# Generated by FakeRAM 2.0
VERSION 5.7 ;
BUSBITCHARS "[]" ;
PROPERTYDEFINITIONS
  MACRO width INTEGER ;
  MACRO depth INTEGER ;
  MACRO banks INTEGER ;
END PROPERTYDEFINITIONS
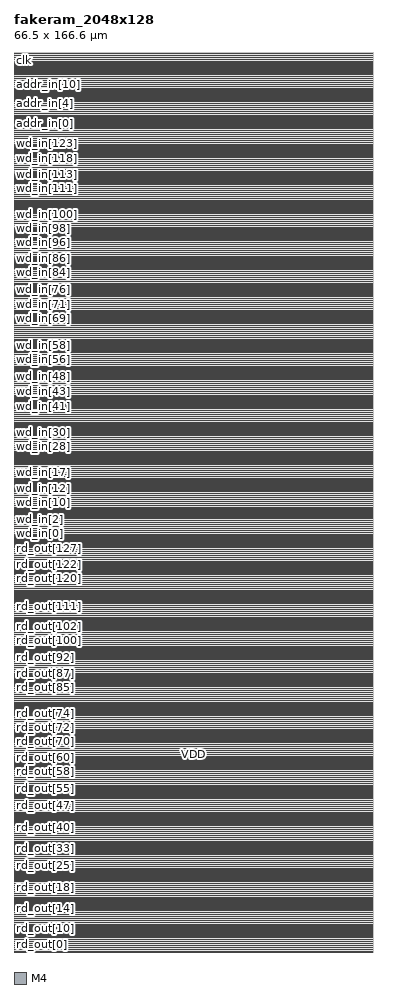
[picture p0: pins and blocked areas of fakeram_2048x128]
MACRO fakeram_2048x128
  PROPERTY width 128 ;
  PROPERTY depth 2048 ;
  PROPERTY banks 4 ;
  FOREIGN fakeram_2048x128 0 0 ;
  SYMMETRY X Y R90 ;
  SIZE 66.500 BY 166.600 ;
  CLASS BLOCK ;
  PIN rd_out[0]
    DIRECTION OUTPUT ;
    USE SIGNAL ;
    SHAPE ABUTMENT ;
    PORT
      LAYER M4 ;
      RECT 0.000 0.048 0.024 0.072 ;
    END
  END rd_out[0]
  PIN rd_out[1]
    DIRECTION OUTPUT ;
    USE SIGNAL ;
    SHAPE ABUTMENT ;
    PORT
      LAYER M4 ;
      RECT 0.000 0.624 0.024 0.648 ;
    END
  END rd_out[1]
  PIN rd_out[2]
    DIRECTION OUTPUT ;
    USE SIGNAL ;
    SHAPE ABUTMENT ;
    PORT
      LAYER M4 ;
      RECT 0.000 1.200 0.024 1.224 ;
    END
  END rd_out[2]
  PIN rd_out[3]
    DIRECTION OUTPUT ;
    USE SIGNAL ;
    SHAPE ABUTMENT ;
    PORT
      LAYER M4 ;
      RECT 0.000 1.776 0.024 1.800 ;
    END
  END rd_out[3]
  PIN rd_out[4]
    DIRECTION OUTPUT ;
    USE SIGNAL ;
    SHAPE ABUTMENT ;
    PORT
      LAYER M4 ;
      RECT 0.000 2.352 0.024 2.376 ;
    END
  END rd_out[4]
  PIN rd_out[5]
    DIRECTION OUTPUT ;
    USE SIGNAL ;
    SHAPE ABUTMENT ;
    PORT
      LAYER M4 ;
      RECT 0.000 2.928 0.024 2.952 ;
    END
  END rd_out[5]
  PIN rd_out[6]
    DIRECTION OUTPUT ;
    USE SIGNAL ;
    SHAPE ABUTMENT ;
    PORT
      LAYER M4 ;
      RECT 0.000 3.504 0.024 3.528 ;
    END
  END rd_out[6]
  PIN rd_out[7]
    DIRECTION OUTPUT ;
    USE SIGNAL ;
    SHAPE ABUTMENT ;
    PORT
      LAYER M4 ;
      RECT 0.000 4.080 0.024 4.104 ;
    END
  END rd_out[7]
  PIN rd_out[8]
    DIRECTION OUTPUT ;
    USE SIGNAL ;
    SHAPE ABUTMENT ;
    PORT
      LAYER M4 ;
      RECT 0.000 4.656 0.024 4.680 ;
    END
  END rd_out[8]
  PIN rd_out[9]
    DIRECTION OUTPUT ;
    USE SIGNAL ;
    SHAPE ABUTMENT ;
    PORT
      LAYER M4 ;
      RECT 0.000 5.232 0.024 5.256 ;
    END
  END rd_out[9]
  PIN rd_out[10]
    DIRECTION OUTPUT ;
    USE SIGNAL ;
    SHAPE ABUTMENT ;
    PORT
      LAYER M4 ;
      RECT 0.000 5.808 0.024 5.832 ;
    END
  END rd_out[10]
  PIN rd_out[11]
    DIRECTION OUTPUT ;
    USE SIGNAL ;
    SHAPE ABUTMENT ;
    PORT
      LAYER M4 ;
      RECT 0.000 6.384 0.024 6.408 ;
    END
  END rd_out[11]
  PIN rd_out[12]
    DIRECTION OUTPUT ;
    USE SIGNAL ;
    SHAPE ABUTMENT ;
    PORT
      LAYER M4 ;
      RECT 0.000 6.960 0.024 6.984 ;
    END
  END rd_out[12]
  PIN rd_out[13]
    DIRECTION OUTPUT ;
    USE SIGNAL ;
    SHAPE ABUTMENT ;
    PORT
      LAYER M4 ;
      RECT 0.000 7.536 0.024 7.560 ;
    END
  END rd_out[13]
  PIN rd_out[14]
    DIRECTION OUTPUT ;
    USE SIGNAL ;
    SHAPE ABUTMENT ;
    PORT
      LAYER M4 ;
      RECT 0.000 8.112 0.024 8.136 ;
    END
  END rd_out[14]
  PIN rd_out[15]
    DIRECTION OUTPUT ;
    USE SIGNAL ;
    SHAPE ABUTMENT ;
    PORT
      LAYER M4 ;
      RECT 0.000 8.688 0.024 8.712 ;
    END
  END rd_out[15]
  PIN rd_out[16]
    DIRECTION OUTPUT ;
    USE SIGNAL ;
    SHAPE ABUTMENT ;
    PORT
      LAYER M4 ;
      RECT 0.000 9.264 0.024 9.288 ;
    END
  END rd_out[16]
  PIN rd_out[17]
    DIRECTION OUTPUT ;
    USE SIGNAL ;
    SHAPE ABUTMENT ;
    PORT
      LAYER M4 ;
      RECT 0.000 9.840 0.024 9.864 ;
    END
  END rd_out[17]
  PIN rd_out[18]
    DIRECTION OUTPUT ;
    USE SIGNAL ;
    SHAPE ABUTMENT ;
    PORT
      LAYER M4 ;
      RECT 0.000 10.416 0.024 10.440 ;
    END
  END rd_out[18]
  PIN rd_out[19]
    DIRECTION OUTPUT ;
    USE SIGNAL ;
    SHAPE ABUTMENT ;
    PORT
      LAYER M4 ;
      RECT 0.000 10.992 0.024 11.016 ;
    END
  END rd_out[19]
  PIN rd_out[20]
    DIRECTION OUTPUT ;
    USE SIGNAL ;
    SHAPE ABUTMENT ;
    PORT
      LAYER M4 ;
      RECT 0.000 11.568 0.024 11.592 ;
    END
  END rd_out[20]
  PIN rd_out[21]
    DIRECTION OUTPUT ;
    USE SIGNAL ;
    SHAPE ABUTMENT ;
    PORT
      LAYER M4 ;
      RECT 0.000 12.144 0.024 12.168 ;
    END
  END rd_out[21]
  PIN rd_out[22]
    DIRECTION OUTPUT ;
    USE SIGNAL ;
    SHAPE ABUTMENT ;
    PORT
      LAYER M4 ;
      RECT 0.000 12.720 0.024 12.744 ;
    END
  END rd_out[22]
  PIN rd_out[23]
    DIRECTION OUTPUT ;
    USE SIGNAL ;
    SHAPE ABUTMENT ;
    PORT
      LAYER M4 ;
      RECT 0.000 13.296 0.024 13.320 ;
    END
  END rd_out[23]
  PIN rd_out[24]
    DIRECTION OUTPUT ;
    USE SIGNAL ;
    SHAPE ABUTMENT ;
    PORT
      LAYER M4 ;
      RECT 0.000 13.872 0.024 13.896 ;
    END
  END rd_out[24]
  PIN rd_out[25]
    DIRECTION OUTPUT ;
    USE SIGNAL ;
    SHAPE ABUTMENT ;
    PORT
      LAYER M4 ;
      RECT 0.000 14.448 0.024 14.472 ;
    END
  END rd_out[25]
  PIN rd_out[26]
    DIRECTION OUTPUT ;
    USE SIGNAL ;
    SHAPE ABUTMENT ;
    PORT
      LAYER M4 ;
      RECT 0.000 15.024 0.024 15.048 ;
    END
  END rd_out[26]
  PIN rd_out[27]
    DIRECTION OUTPUT ;
    USE SIGNAL ;
    SHAPE ABUTMENT ;
    PORT
      LAYER M4 ;
      RECT 0.000 15.600 0.024 15.624 ;
    END
  END rd_out[27]
  PIN rd_out[28]
    DIRECTION OUTPUT ;
    USE SIGNAL ;
    SHAPE ABUTMENT ;
    PORT
      LAYER M4 ;
      RECT 0.000 16.176 0.024 16.200 ;
    END
  END rd_out[28]
  PIN rd_out[29]
    DIRECTION OUTPUT ;
    USE SIGNAL ;
    SHAPE ABUTMENT ;
    PORT
      LAYER M4 ;
      RECT 0.000 16.752 0.024 16.776 ;
    END
  END rd_out[29]
  PIN rd_out[30]
    DIRECTION OUTPUT ;
    USE SIGNAL ;
    SHAPE ABUTMENT ;
    PORT
      LAYER M4 ;
      RECT 0.000 17.328 0.024 17.352 ;
    END
  END rd_out[30]
  PIN rd_out[31]
    DIRECTION OUTPUT ;
    USE SIGNAL ;
    SHAPE ABUTMENT ;
    PORT
      LAYER M4 ;
      RECT 0.000 17.904 0.024 17.928 ;
    END
  END rd_out[31]
  PIN rd_out[32]
    DIRECTION OUTPUT ;
    USE SIGNAL ;
    SHAPE ABUTMENT ;
    PORT
      LAYER M4 ;
      RECT 0.000 18.480 0.024 18.504 ;
    END
  END rd_out[32]
  PIN rd_out[33]
    DIRECTION OUTPUT ;
    USE SIGNAL ;
    SHAPE ABUTMENT ;
    PORT
      LAYER M4 ;
      RECT 0.000 19.056 0.024 19.080 ;
    END
  END rd_out[33]
  PIN rd_out[34]
    DIRECTION OUTPUT ;
    USE SIGNAL ;
    SHAPE ABUTMENT ;
    PORT
      LAYER M4 ;
      RECT 0.000 19.632 0.024 19.656 ;
    END
  END rd_out[34]
  PIN rd_out[35]
    DIRECTION OUTPUT ;
    USE SIGNAL ;
    SHAPE ABUTMENT ;
    PORT
      LAYER M4 ;
      RECT 0.000 20.208 0.024 20.232 ;
    END
  END rd_out[35]
  PIN rd_out[36]
    DIRECTION OUTPUT ;
    USE SIGNAL ;
    SHAPE ABUTMENT ;
    PORT
      LAYER M4 ;
      RECT 0.000 20.784 0.024 20.808 ;
    END
  END rd_out[36]
  PIN rd_out[37]
    DIRECTION OUTPUT ;
    USE SIGNAL ;
    SHAPE ABUTMENT ;
    PORT
      LAYER M4 ;
      RECT 0.000 21.360 0.024 21.384 ;
    END
  END rd_out[37]
  PIN rd_out[38]
    DIRECTION OUTPUT ;
    USE SIGNAL ;
    SHAPE ABUTMENT ;
    PORT
      LAYER M4 ;
      RECT 0.000 21.936 0.024 21.960 ;
    END
  END rd_out[38]
  PIN rd_out[39]
    DIRECTION OUTPUT ;
    USE SIGNAL ;
    SHAPE ABUTMENT ;
    PORT
      LAYER M4 ;
      RECT 0.000 22.512 0.024 22.536 ;
    END
  END rd_out[39]
  PIN rd_out[40]
    DIRECTION OUTPUT ;
    USE SIGNAL ;
    SHAPE ABUTMENT ;
    PORT
      LAYER M4 ;
      RECT 0.000 23.088 0.024 23.112 ;
    END
  END rd_out[40]
  PIN rd_out[41]
    DIRECTION OUTPUT ;
    USE SIGNAL ;
    SHAPE ABUTMENT ;
    PORT
      LAYER M4 ;
      RECT 0.000 23.664 0.024 23.688 ;
    END
  END rd_out[41]
  PIN rd_out[42]
    DIRECTION OUTPUT ;
    USE SIGNAL ;
    SHAPE ABUTMENT ;
    PORT
      LAYER M4 ;
      RECT 0.000 24.240 0.024 24.264 ;
    END
  END rd_out[42]
  PIN rd_out[43]
    DIRECTION OUTPUT ;
    USE SIGNAL ;
    SHAPE ABUTMENT ;
    PORT
      LAYER M4 ;
      RECT 0.000 24.816 0.024 24.840 ;
    END
  END rd_out[43]
  PIN rd_out[44]
    DIRECTION OUTPUT ;
    USE SIGNAL ;
    SHAPE ABUTMENT ;
    PORT
      LAYER M4 ;
      RECT 0.000 25.392 0.024 25.416 ;
    END
  END rd_out[44]
  PIN rd_out[45]
    DIRECTION OUTPUT ;
    USE SIGNAL ;
    SHAPE ABUTMENT ;
    PORT
      LAYER M4 ;
      RECT 0.000 25.968 0.024 25.992 ;
    END
  END rd_out[45]
  PIN rd_out[46]
    DIRECTION OUTPUT ;
    USE SIGNAL ;
    SHAPE ABUTMENT ;
    PORT
      LAYER M4 ;
      RECT 0.000 26.544 0.024 26.568 ;
    END
  END rd_out[46]
  PIN rd_out[47]
    DIRECTION OUTPUT ;
    USE SIGNAL ;
    SHAPE ABUTMENT ;
    PORT
      LAYER M4 ;
      RECT 0.000 27.120 0.024 27.144 ;
    END
  END rd_out[47]
  PIN rd_out[48]
    DIRECTION OUTPUT ;
    USE SIGNAL ;
    SHAPE ABUTMENT ;
    PORT
      LAYER M4 ;
      RECT 0.000 27.696 0.024 27.720 ;
    END
  END rd_out[48]
  PIN rd_out[49]
    DIRECTION OUTPUT ;
    USE SIGNAL ;
    SHAPE ABUTMENT ;
    PORT
      LAYER M4 ;
      RECT 0.000 28.272 0.024 28.296 ;
    END
  END rd_out[49]
  PIN rd_out[50]
    DIRECTION OUTPUT ;
    USE SIGNAL ;
    SHAPE ABUTMENT ;
    PORT
      LAYER M4 ;
      RECT 0.000 28.848 0.024 28.872 ;
    END
  END rd_out[50]
  PIN rd_out[51]
    DIRECTION OUTPUT ;
    USE SIGNAL ;
    SHAPE ABUTMENT ;
    PORT
      LAYER M4 ;
      RECT 0.000 29.424 0.024 29.448 ;
    END
  END rd_out[51]
  PIN rd_out[52]
    DIRECTION OUTPUT ;
    USE SIGNAL ;
    SHAPE ABUTMENT ;
    PORT
      LAYER M4 ;
      RECT 0.000 30.000 0.024 30.024 ;
    END
  END rd_out[52]
  PIN rd_out[53]
    DIRECTION OUTPUT ;
    USE SIGNAL ;
    SHAPE ABUTMENT ;
    PORT
      LAYER M4 ;
      RECT 0.000 30.576 0.024 30.600 ;
    END
  END rd_out[53]
  PIN rd_out[54]
    DIRECTION OUTPUT ;
    USE SIGNAL ;
    SHAPE ABUTMENT ;
    PORT
      LAYER M4 ;
      RECT 0.000 31.152 0.024 31.176 ;
    END
  END rd_out[54]
  PIN rd_out[55]
    DIRECTION OUTPUT ;
    USE SIGNAL ;
    SHAPE ABUTMENT ;
    PORT
      LAYER M4 ;
      RECT 0.000 31.728 0.024 31.752 ;
    END
  END rd_out[55]
  PIN rd_out[56]
    DIRECTION OUTPUT ;
    USE SIGNAL ;
    SHAPE ABUTMENT ;
    PORT
      LAYER M4 ;
      RECT 0.000 32.304 0.024 32.328 ;
    END
  END rd_out[56]
  PIN rd_out[57]
    DIRECTION OUTPUT ;
    USE SIGNAL ;
    SHAPE ABUTMENT ;
    PORT
      LAYER M4 ;
      RECT 0.000 32.880 0.024 32.904 ;
    END
  END rd_out[57]
  PIN rd_out[58]
    DIRECTION OUTPUT ;
    USE SIGNAL ;
    SHAPE ABUTMENT ;
    PORT
      LAYER M4 ;
      RECT 0.000 33.456 0.024 33.480 ;
    END
  END rd_out[58]
  PIN rd_out[59]
    DIRECTION OUTPUT ;
    USE SIGNAL ;
    SHAPE ABUTMENT ;
    PORT
      LAYER M4 ;
      RECT 0.000 34.032 0.024 34.056 ;
    END
  END rd_out[59]
  PIN rd_out[60]
    DIRECTION OUTPUT ;
    USE SIGNAL ;
    SHAPE ABUTMENT ;
    PORT
      LAYER M4 ;
      RECT 0.000 34.608 0.024 34.632 ;
    END
  END rd_out[60]
  PIN rd_out[61]
    DIRECTION OUTPUT ;
    USE SIGNAL ;
    SHAPE ABUTMENT ;
    PORT
      LAYER M4 ;
      RECT 0.000 35.184 0.024 35.208 ;
    END
  END rd_out[61]
  PIN rd_out[62]
    DIRECTION OUTPUT ;
    USE SIGNAL ;
    SHAPE ABUTMENT ;
    PORT
      LAYER M4 ;
      RECT 0.000 35.760 0.024 35.784 ;
    END
  END rd_out[62]
  PIN rd_out[63]
    DIRECTION OUTPUT ;
    USE SIGNAL ;
    SHAPE ABUTMENT ;
    PORT
      LAYER M4 ;
      RECT 0.000 36.336 0.024 36.360 ;
    END
  END rd_out[63]
  PIN rd_out[64]
    DIRECTION OUTPUT ;
    USE SIGNAL ;
    SHAPE ABUTMENT ;
    PORT
      LAYER M4 ;
      RECT 0.000 36.912 0.024 36.936 ;
    END
  END rd_out[64]
  PIN rd_out[65]
    DIRECTION OUTPUT ;
    USE SIGNAL ;
    SHAPE ABUTMENT ;
    PORT
      LAYER M4 ;
      RECT 0.000 37.488 0.024 37.512 ;
    END
  END rd_out[65]
  PIN rd_out[66]
    DIRECTION OUTPUT ;
    USE SIGNAL ;
    SHAPE ABUTMENT ;
    PORT
      LAYER M4 ;
      RECT 0.000 38.064 0.024 38.088 ;
    END
  END rd_out[66]
  PIN rd_out[67]
    DIRECTION OUTPUT ;
    USE SIGNAL ;
    SHAPE ABUTMENT ;
    PORT
      LAYER M4 ;
      RECT 0.000 38.640 0.024 38.664 ;
    END
  END rd_out[67]
  PIN rd_out[68]
    DIRECTION OUTPUT ;
    USE SIGNAL ;
    SHAPE ABUTMENT ;
    PORT
      LAYER M4 ;
      RECT 0.000 39.216 0.024 39.240 ;
    END
  END rd_out[68]
  PIN rd_out[69]
    DIRECTION OUTPUT ;
    USE SIGNAL ;
    SHAPE ABUTMENT ;
    PORT
      LAYER M4 ;
      RECT 0.000 39.792 0.024 39.816 ;
    END
  END rd_out[69]
  PIN rd_out[70]
    DIRECTION OUTPUT ;
    USE SIGNAL ;
    SHAPE ABUTMENT ;
    PORT
      LAYER M4 ;
      RECT 0.000 40.368 0.024 40.392 ;
    END
  END rd_out[70]
  PIN rd_out[71]
    DIRECTION OUTPUT ;
    USE SIGNAL ;
    SHAPE ABUTMENT ;
    PORT
      LAYER M4 ;
      RECT 0.000 40.944 0.024 40.968 ;
    END
  END rd_out[71]
  PIN rd_out[72]
    DIRECTION OUTPUT ;
    USE SIGNAL ;
    SHAPE ABUTMENT ;
    PORT
      LAYER M4 ;
      RECT 0.000 41.520 0.024 41.544 ;
    END
  END rd_out[72]
  PIN rd_out[73]
    DIRECTION OUTPUT ;
    USE SIGNAL ;
    SHAPE ABUTMENT ;
    PORT
      LAYER M4 ;
      RECT 0.000 42.096 0.024 42.120 ;
    END
  END rd_out[73]
  PIN rd_out[74]
    DIRECTION OUTPUT ;
    USE SIGNAL ;
    SHAPE ABUTMENT ;
    PORT
      LAYER M4 ;
      RECT 0.000 42.672 0.024 42.696 ;
    END
  END rd_out[74]
  PIN rd_out[75]
    DIRECTION OUTPUT ;
    USE SIGNAL ;
    SHAPE ABUTMENT ;
    PORT
      LAYER M4 ;
      RECT 0.000 43.248 0.024 43.272 ;
    END
  END rd_out[75]
  PIN rd_out[76]
    DIRECTION OUTPUT ;
    USE SIGNAL ;
    SHAPE ABUTMENT ;
    PORT
      LAYER M4 ;
      RECT 0.000 43.824 0.024 43.848 ;
    END
  END rd_out[76]
  PIN rd_out[77]
    DIRECTION OUTPUT ;
    USE SIGNAL ;
    SHAPE ABUTMENT ;
    PORT
      LAYER M4 ;
      RECT 0.000 44.400 0.024 44.424 ;
    END
  END rd_out[77]
  PIN rd_out[78]
    DIRECTION OUTPUT ;
    USE SIGNAL ;
    SHAPE ABUTMENT ;
    PORT
      LAYER M4 ;
      RECT 0.000 44.976 0.024 45.000 ;
    END
  END rd_out[78]
  PIN rd_out[79]
    DIRECTION OUTPUT ;
    USE SIGNAL ;
    SHAPE ABUTMENT ;
    PORT
      LAYER M4 ;
      RECT 0.000 45.552 0.024 45.576 ;
    END
  END rd_out[79]
  PIN rd_out[80]
    DIRECTION OUTPUT ;
    USE SIGNAL ;
    SHAPE ABUTMENT ;
    PORT
      LAYER M4 ;
      RECT 0.000 46.128 0.024 46.152 ;
    END
  END rd_out[80]
  PIN rd_out[81]
    DIRECTION OUTPUT ;
    USE SIGNAL ;
    SHAPE ABUTMENT ;
    PORT
      LAYER M4 ;
      RECT 0.000 46.704 0.024 46.728 ;
    END
  END rd_out[81]
  PIN rd_out[82]
    DIRECTION OUTPUT ;
    USE SIGNAL ;
    SHAPE ABUTMENT ;
    PORT
      LAYER M4 ;
      RECT 0.000 47.280 0.024 47.304 ;
    END
  END rd_out[82]
  PIN rd_out[83]
    DIRECTION OUTPUT ;
    USE SIGNAL ;
    SHAPE ABUTMENT ;
    PORT
      LAYER M4 ;
      RECT 0.000 47.856 0.024 47.880 ;
    END
  END rd_out[83]
  PIN rd_out[84]
    DIRECTION OUTPUT ;
    USE SIGNAL ;
    SHAPE ABUTMENT ;
    PORT
      LAYER M4 ;
      RECT 0.000 48.432 0.024 48.456 ;
    END
  END rd_out[84]
  PIN rd_out[85]
    DIRECTION OUTPUT ;
    USE SIGNAL ;
    SHAPE ABUTMENT ;
    PORT
      LAYER M4 ;
      RECT 0.000 49.008 0.024 49.032 ;
    END
  END rd_out[85]
  PIN rd_out[86]
    DIRECTION OUTPUT ;
    USE SIGNAL ;
    SHAPE ABUTMENT ;
    PORT
      LAYER M4 ;
      RECT 0.000 49.584 0.024 49.608 ;
    END
  END rd_out[86]
  PIN rd_out[87]
    DIRECTION OUTPUT ;
    USE SIGNAL ;
    SHAPE ABUTMENT ;
    PORT
      LAYER M4 ;
      RECT 0.000 50.160 0.024 50.184 ;
    END
  END rd_out[87]
  PIN rd_out[88]
    DIRECTION OUTPUT ;
    USE SIGNAL ;
    SHAPE ABUTMENT ;
    PORT
      LAYER M4 ;
      RECT 0.000 50.736 0.024 50.760 ;
    END
  END rd_out[88]
  PIN rd_out[89]
    DIRECTION OUTPUT ;
    USE SIGNAL ;
    SHAPE ABUTMENT ;
    PORT
      LAYER M4 ;
      RECT 0.000 51.312 0.024 51.336 ;
    END
  END rd_out[89]
  PIN rd_out[90]
    DIRECTION OUTPUT ;
    USE SIGNAL ;
    SHAPE ABUTMENT ;
    PORT
      LAYER M4 ;
      RECT 0.000 51.888 0.024 51.912 ;
    END
  END rd_out[90]
  PIN rd_out[91]
    DIRECTION OUTPUT ;
    USE SIGNAL ;
    SHAPE ABUTMENT ;
    PORT
      LAYER M4 ;
      RECT 0.000 52.464 0.024 52.488 ;
    END
  END rd_out[91]
  PIN rd_out[92]
    DIRECTION OUTPUT ;
    USE SIGNAL ;
    SHAPE ABUTMENT ;
    PORT
      LAYER M4 ;
      RECT 0.000 53.040 0.024 53.064 ;
    END
  END rd_out[92]
  PIN rd_out[93]
    DIRECTION OUTPUT ;
    USE SIGNAL ;
    SHAPE ABUTMENT ;
    PORT
      LAYER M4 ;
      RECT 0.000 53.616 0.024 53.640 ;
    END
  END rd_out[93]
  PIN rd_out[94]
    DIRECTION OUTPUT ;
    USE SIGNAL ;
    SHAPE ABUTMENT ;
    PORT
      LAYER M4 ;
      RECT 0.000 54.192 0.024 54.216 ;
    END
  END rd_out[94]
  PIN rd_out[95]
    DIRECTION OUTPUT ;
    USE SIGNAL ;
    SHAPE ABUTMENT ;
    PORT
      LAYER M4 ;
      RECT 0.000 54.768 0.024 54.792 ;
    END
  END rd_out[95]
  PIN rd_out[96]
    DIRECTION OUTPUT ;
    USE SIGNAL ;
    SHAPE ABUTMENT ;
    PORT
      LAYER M4 ;
      RECT 0.000 55.344 0.024 55.368 ;
    END
  END rd_out[96]
  PIN rd_out[97]
    DIRECTION OUTPUT ;
    USE SIGNAL ;
    SHAPE ABUTMENT ;
    PORT
      LAYER M4 ;
      RECT 0.000 55.920 0.024 55.944 ;
    END
  END rd_out[97]
  PIN rd_out[98]
    DIRECTION OUTPUT ;
    USE SIGNAL ;
    SHAPE ABUTMENT ;
    PORT
      LAYER M4 ;
      RECT 0.000 56.496 0.024 56.520 ;
    END
  END rd_out[98]
  PIN rd_out[99]
    DIRECTION OUTPUT ;
    USE SIGNAL ;
    SHAPE ABUTMENT ;
    PORT
      LAYER M4 ;
      RECT 0.000 57.072 0.024 57.096 ;
    END
  END rd_out[99]
  PIN rd_out[100]
    DIRECTION OUTPUT ;
    USE SIGNAL ;
    SHAPE ABUTMENT ;
    PORT
      LAYER M4 ;
      RECT 0.000 57.648 0.024 57.672 ;
    END
  END rd_out[100]
  PIN rd_out[101]
    DIRECTION OUTPUT ;
    USE SIGNAL ;
    SHAPE ABUTMENT ;
    PORT
      LAYER M4 ;
      RECT 0.000 58.224 0.024 58.248 ;
    END
  END rd_out[101]
  PIN rd_out[102]
    DIRECTION OUTPUT ;
    USE SIGNAL ;
    SHAPE ABUTMENT ;
    PORT
      LAYER M4 ;
      RECT 0.000 58.800 0.024 58.824 ;
    END
  END rd_out[102]
  PIN rd_out[103]
    DIRECTION OUTPUT ;
    USE SIGNAL ;
    SHAPE ABUTMENT ;
    PORT
      LAYER M4 ;
      RECT 0.000 59.376 0.024 59.400 ;
    END
  END rd_out[103]
  PIN rd_out[104]
    DIRECTION OUTPUT ;
    USE SIGNAL ;
    SHAPE ABUTMENT ;
    PORT
      LAYER M4 ;
      RECT 0.000 59.952 0.024 59.976 ;
    END
  END rd_out[104]
  PIN rd_out[105]
    DIRECTION OUTPUT ;
    USE SIGNAL ;
    SHAPE ABUTMENT ;
    PORT
      LAYER M4 ;
      RECT 0.000 60.528 0.024 60.552 ;
    END
  END rd_out[105]
  PIN rd_out[106]
    DIRECTION OUTPUT ;
    USE SIGNAL ;
    SHAPE ABUTMENT ;
    PORT
      LAYER M4 ;
      RECT 0.000 61.104 0.024 61.128 ;
    END
  END rd_out[106]
  PIN rd_out[107]
    DIRECTION OUTPUT ;
    USE SIGNAL ;
    SHAPE ABUTMENT ;
    PORT
      LAYER M4 ;
      RECT 0.000 61.680 0.024 61.704 ;
    END
  END rd_out[107]
  PIN rd_out[108]
    DIRECTION OUTPUT ;
    USE SIGNAL ;
    SHAPE ABUTMENT ;
    PORT
      LAYER M4 ;
      RECT 0.000 62.256 0.024 62.280 ;
    END
  END rd_out[108]
  PIN rd_out[109]
    DIRECTION OUTPUT ;
    USE SIGNAL ;
    SHAPE ABUTMENT ;
    PORT
      LAYER M4 ;
      RECT 0.000 62.832 0.024 62.856 ;
    END
  END rd_out[109]
  PIN rd_out[110]
    DIRECTION OUTPUT ;
    USE SIGNAL ;
    SHAPE ABUTMENT ;
    PORT
      LAYER M4 ;
      RECT 0.000 63.408 0.024 63.432 ;
    END
  END rd_out[110]
  PIN rd_out[111]
    DIRECTION OUTPUT ;
    USE SIGNAL ;
    SHAPE ABUTMENT ;
    PORT
      LAYER M4 ;
      RECT 0.000 63.984 0.024 64.008 ;
    END
  END rd_out[111]
  PIN rd_out[112]
    DIRECTION OUTPUT ;
    USE SIGNAL ;
    SHAPE ABUTMENT ;
    PORT
      LAYER M4 ;
      RECT 0.000 64.560 0.024 64.584 ;
    END
  END rd_out[112]
  PIN rd_out[113]
    DIRECTION OUTPUT ;
    USE SIGNAL ;
    SHAPE ABUTMENT ;
    PORT
      LAYER M4 ;
      RECT 0.000 65.136 0.024 65.160 ;
    END
  END rd_out[113]
  PIN rd_out[114]
    DIRECTION OUTPUT ;
    USE SIGNAL ;
    SHAPE ABUTMENT ;
    PORT
      LAYER M4 ;
      RECT 0.000 65.712 0.024 65.736 ;
    END
  END rd_out[114]
  PIN rd_out[115]
    DIRECTION OUTPUT ;
    USE SIGNAL ;
    SHAPE ABUTMENT ;
    PORT
      LAYER M4 ;
      RECT 0.000 66.288 0.024 66.312 ;
    END
  END rd_out[115]
  PIN rd_out[116]
    DIRECTION OUTPUT ;
    USE SIGNAL ;
    SHAPE ABUTMENT ;
    PORT
      LAYER M4 ;
      RECT 0.000 66.864 0.024 66.888 ;
    END
  END rd_out[116]
  PIN rd_out[117]
    DIRECTION OUTPUT ;
    USE SIGNAL ;
    SHAPE ABUTMENT ;
    PORT
      LAYER M4 ;
      RECT 0.000 67.440 0.024 67.464 ;
    END
  END rd_out[117]
  PIN rd_out[118]
    DIRECTION OUTPUT ;
    USE SIGNAL ;
    SHAPE ABUTMENT ;
    PORT
      LAYER M4 ;
      RECT 0.000 68.016 0.024 68.040 ;
    END
  END rd_out[118]
  PIN rd_out[119]
    DIRECTION OUTPUT ;
    USE SIGNAL ;
    SHAPE ABUTMENT ;
    PORT
      LAYER M4 ;
      RECT 0.000 68.592 0.024 68.616 ;
    END
  END rd_out[119]
  PIN rd_out[120]
    DIRECTION OUTPUT ;
    USE SIGNAL ;
    SHAPE ABUTMENT ;
    PORT
      LAYER M4 ;
      RECT 0.000 69.168 0.024 69.192 ;
    END
  END rd_out[120]
  PIN rd_out[121]
    DIRECTION OUTPUT ;
    USE SIGNAL ;
    SHAPE ABUTMENT ;
    PORT
      LAYER M4 ;
      RECT 0.000 69.744 0.024 69.768 ;
    END
  END rd_out[121]
  PIN rd_out[122]
    DIRECTION OUTPUT ;
    USE SIGNAL ;
    SHAPE ABUTMENT ;
    PORT
      LAYER M4 ;
      RECT 0.000 70.320 0.024 70.344 ;
    END
  END rd_out[122]
  PIN rd_out[123]
    DIRECTION OUTPUT ;
    USE SIGNAL ;
    SHAPE ABUTMENT ;
    PORT
      LAYER M4 ;
      RECT 0.000 70.896 0.024 70.920 ;
    END
  END rd_out[123]
  PIN rd_out[124]
    DIRECTION OUTPUT ;
    USE SIGNAL ;
    SHAPE ABUTMENT ;
    PORT
      LAYER M4 ;
      RECT 0.000 71.472 0.024 71.496 ;
    END
  END rd_out[124]
  PIN rd_out[125]
    DIRECTION OUTPUT ;
    USE SIGNAL ;
    SHAPE ABUTMENT ;
    PORT
      LAYER M4 ;
      RECT 0.000 72.048 0.024 72.072 ;
    END
  END rd_out[125]
  PIN rd_out[126]
    DIRECTION OUTPUT ;
    USE SIGNAL ;
    SHAPE ABUTMENT ;
    PORT
      LAYER M4 ;
      RECT 0.000 72.624 0.024 72.648 ;
    END
  END rd_out[126]
  PIN rd_out[127]
    DIRECTION OUTPUT ;
    USE SIGNAL ;
    SHAPE ABUTMENT ;
    PORT
      LAYER M4 ;
      RECT 0.000 73.200 0.024 73.224 ;
    END
  END rd_out[127]
  PIN wd_in[0]
    DIRECTION INPUT ;
    USE SIGNAL ;
    SHAPE ABUTMENT ;
    PORT
      LAYER M4 ;
      RECT 0.000 77.424 0.024 77.448 ;
    END
  END wd_in[0]
  PIN wd_in[1]
    DIRECTION INPUT ;
    USE SIGNAL ;
    SHAPE ABUTMENT ;
    PORT
      LAYER M4 ;
      RECT 0.000 78.000 0.024 78.024 ;
    END
  END wd_in[1]
  PIN wd_in[2]
    DIRECTION INPUT ;
    USE SIGNAL ;
    SHAPE ABUTMENT ;
    PORT
      LAYER M4 ;
      RECT 0.000 78.576 0.024 78.600 ;
    END
  END wd_in[2]
  PIN wd_in[3]
    DIRECTION INPUT ;
    USE SIGNAL ;
    SHAPE ABUTMENT ;
    PORT
      LAYER M4 ;
      RECT 0.000 79.152 0.024 79.176 ;
    END
  END wd_in[3]
  PIN wd_in[4]
    DIRECTION INPUT ;
    USE SIGNAL ;
    SHAPE ABUTMENT ;
    PORT
      LAYER M4 ;
      RECT 0.000 79.728 0.024 79.752 ;
    END
  END wd_in[4]
  PIN wd_in[5]
    DIRECTION INPUT ;
    USE SIGNAL ;
    SHAPE ABUTMENT ;
    PORT
      LAYER M4 ;
      RECT 0.000 80.304 0.024 80.328 ;
    END
  END wd_in[5]
  PIN wd_in[6]
    DIRECTION INPUT ;
    USE SIGNAL ;
    SHAPE ABUTMENT ;
    PORT
      LAYER M4 ;
      RECT 0.000 80.880 0.024 80.904 ;
    END
  END wd_in[6]
  PIN wd_in[7]
    DIRECTION INPUT ;
    USE SIGNAL ;
    SHAPE ABUTMENT ;
    PORT
      LAYER M4 ;
      RECT 0.000 81.456 0.024 81.480 ;
    END
  END wd_in[7]
  PIN wd_in[8]
    DIRECTION INPUT ;
    USE SIGNAL ;
    SHAPE ABUTMENT ;
    PORT
      LAYER M4 ;
      RECT 0.000 82.032 0.024 82.056 ;
    END
  END wd_in[8]
  PIN wd_in[9]
    DIRECTION INPUT ;
    USE SIGNAL ;
    SHAPE ABUTMENT ;
    PORT
      LAYER M4 ;
      RECT 0.000 82.608 0.024 82.632 ;
    END
  END wd_in[9]
  PIN wd_in[10]
    DIRECTION INPUT ;
    USE SIGNAL ;
    SHAPE ABUTMENT ;
    PORT
      LAYER M4 ;
      RECT 0.000 83.184 0.024 83.208 ;
    END
  END wd_in[10]
  PIN wd_in[11]
    DIRECTION INPUT ;
    USE SIGNAL ;
    SHAPE ABUTMENT ;
    PORT
      LAYER M4 ;
      RECT 0.000 83.760 0.024 83.784 ;
    END
  END wd_in[11]
  PIN wd_in[12]
    DIRECTION INPUT ;
    USE SIGNAL ;
    SHAPE ABUTMENT ;
    PORT
      LAYER M4 ;
      RECT 0.000 84.336 0.024 84.360 ;
    END
  END wd_in[12]
  PIN wd_in[13]
    DIRECTION INPUT ;
    USE SIGNAL ;
    SHAPE ABUTMENT ;
    PORT
      LAYER M4 ;
      RECT 0.000 84.912 0.024 84.936 ;
    END
  END wd_in[13]
  PIN wd_in[14]
    DIRECTION INPUT ;
    USE SIGNAL ;
    SHAPE ABUTMENT ;
    PORT
      LAYER M4 ;
      RECT 0.000 85.488 0.024 85.512 ;
    END
  END wd_in[14]
  PIN wd_in[15]
    DIRECTION INPUT ;
    USE SIGNAL ;
    SHAPE ABUTMENT ;
    PORT
      LAYER M4 ;
      RECT 0.000 86.064 0.024 86.088 ;
    END
  END wd_in[15]
  PIN wd_in[16]
    DIRECTION INPUT ;
    USE SIGNAL ;
    SHAPE ABUTMENT ;
    PORT
      LAYER M4 ;
      RECT 0.000 86.640 0.024 86.664 ;
    END
  END wd_in[16]
  PIN wd_in[17]
    DIRECTION INPUT ;
    USE SIGNAL ;
    SHAPE ABUTMENT ;
    PORT
      LAYER M4 ;
      RECT 0.000 87.216 0.024 87.240 ;
    END
  END wd_in[17]
  PIN wd_in[18]
    DIRECTION INPUT ;
    USE SIGNAL ;
    SHAPE ABUTMENT ;
    PORT
      LAYER M4 ;
      RECT 0.000 87.792 0.024 87.816 ;
    END
  END wd_in[18]
  PIN wd_in[19]
    DIRECTION INPUT ;
    USE SIGNAL ;
    SHAPE ABUTMENT ;
    PORT
      LAYER M4 ;
      RECT 0.000 88.368 0.024 88.392 ;
    END
  END wd_in[19]
  PIN wd_in[20]
    DIRECTION INPUT ;
    USE SIGNAL ;
    SHAPE ABUTMENT ;
    PORT
      LAYER M4 ;
      RECT 0.000 88.944 0.024 88.968 ;
    END
  END wd_in[20]
  PIN wd_in[21]
    DIRECTION INPUT ;
    USE SIGNAL ;
    SHAPE ABUTMENT ;
    PORT
      LAYER M4 ;
      RECT 0.000 89.520 0.024 89.544 ;
    END
  END wd_in[21]
  PIN wd_in[22]
    DIRECTION INPUT ;
    USE SIGNAL ;
    SHAPE ABUTMENT ;
    PORT
      LAYER M4 ;
      RECT 0.000 90.096 0.024 90.120 ;
    END
  END wd_in[22]
  PIN wd_in[23]
    DIRECTION INPUT ;
    USE SIGNAL ;
    SHAPE ABUTMENT ;
    PORT
      LAYER M4 ;
      RECT 0.000 90.672 0.024 90.696 ;
    END
  END wd_in[23]
  PIN wd_in[24]
    DIRECTION INPUT ;
    USE SIGNAL ;
    SHAPE ABUTMENT ;
    PORT
      LAYER M4 ;
      RECT 0.000 91.248 0.024 91.272 ;
    END
  END wd_in[24]
  PIN wd_in[25]
    DIRECTION INPUT ;
    USE SIGNAL ;
    SHAPE ABUTMENT ;
    PORT
      LAYER M4 ;
      RECT 0.000 91.824 0.024 91.848 ;
    END
  END wd_in[25]
  PIN wd_in[26]
    DIRECTION INPUT ;
    USE SIGNAL ;
    SHAPE ABUTMENT ;
    PORT
      LAYER M4 ;
      RECT 0.000 92.400 0.024 92.424 ;
    END
  END wd_in[26]
  PIN wd_in[27]
    DIRECTION INPUT ;
    USE SIGNAL ;
    SHAPE ABUTMENT ;
    PORT
      LAYER M4 ;
      RECT 0.000 92.976 0.024 93.000 ;
    END
  END wd_in[27]
  PIN wd_in[28]
    DIRECTION INPUT ;
    USE SIGNAL ;
    SHAPE ABUTMENT ;
    PORT
      LAYER M4 ;
      RECT 0.000 93.552 0.024 93.576 ;
    END
  END wd_in[28]
  PIN wd_in[29]
    DIRECTION INPUT ;
    USE SIGNAL ;
    SHAPE ABUTMENT ;
    PORT
      LAYER M4 ;
      RECT 0.000 94.128 0.024 94.152 ;
    END
  END wd_in[29]
  PIN wd_in[30]
    DIRECTION INPUT ;
    USE SIGNAL ;
    SHAPE ABUTMENT ;
    PORT
      LAYER M4 ;
      RECT 0.000 94.704 0.024 94.728 ;
    END
  END wd_in[30]
  PIN wd_in[31]
    DIRECTION INPUT ;
    USE SIGNAL ;
    SHAPE ABUTMENT ;
    PORT
      LAYER M4 ;
      RECT 0.000 95.280 0.024 95.304 ;
    END
  END wd_in[31]
  PIN wd_in[32]
    DIRECTION INPUT ;
    USE SIGNAL ;
    SHAPE ABUTMENT ;
    PORT
      LAYER M4 ;
      RECT 0.000 95.856 0.024 95.880 ;
    END
  END wd_in[32]
  PIN wd_in[33]
    DIRECTION INPUT ;
    USE SIGNAL ;
    SHAPE ABUTMENT ;
    PORT
      LAYER M4 ;
      RECT 0.000 96.432 0.024 96.456 ;
    END
  END wd_in[33]
  PIN wd_in[34]
    DIRECTION INPUT ;
    USE SIGNAL ;
    SHAPE ABUTMENT ;
    PORT
      LAYER M4 ;
      RECT 0.000 97.008 0.024 97.032 ;
    END
  END wd_in[34]
  PIN wd_in[35]
    DIRECTION INPUT ;
    USE SIGNAL ;
    SHAPE ABUTMENT ;
    PORT
      LAYER M4 ;
      RECT 0.000 97.584 0.024 97.608 ;
    END
  END wd_in[35]
  PIN wd_in[36]
    DIRECTION INPUT ;
    USE SIGNAL ;
    SHAPE ABUTMENT ;
    PORT
      LAYER M4 ;
      RECT 0.000 98.160 0.024 98.184 ;
    END
  END wd_in[36]
  PIN wd_in[37]
    DIRECTION INPUT ;
    USE SIGNAL ;
    SHAPE ABUTMENT ;
    PORT
      LAYER M4 ;
      RECT 0.000 98.736 0.024 98.760 ;
    END
  END wd_in[37]
  PIN wd_in[38]
    DIRECTION INPUT ;
    USE SIGNAL ;
    SHAPE ABUTMENT ;
    PORT
      LAYER M4 ;
      RECT 0.000 99.312 0.024 99.336 ;
    END
  END wd_in[38]
  PIN wd_in[39]
    DIRECTION INPUT ;
    USE SIGNAL ;
    SHAPE ABUTMENT ;
    PORT
      LAYER M4 ;
      RECT 0.000 99.888 0.024 99.912 ;
    END
  END wd_in[39]
  PIN wd_in[40]
    DIRECTION INPUT ;
    USE SIGNAL ;
    SHAPE ABUTMENT ;
    PORT
      LAYER M4 ;
      RECT 0.000 100.464 0.024 100.488 ;
    END
  END wd_in[40]
  PIN wd_in[41]
    DIRECTION INPUT ;
    USE SIGNAL ;
    SHAPE ABUTMENT ;
    PORT
      LAYER M4 ;
      RECT 0.000 101.040 0.024 101.064 ;
    END
  END wd_in[41]
  PIN wd_in[42]
    DIRECTION INPUT ;
    USE SIGNAL ;
    SHAPE ABUTMENT ;
    PORT
      LAYER M4 ;
      RECT 0.000 101.616 0.024 101.640 ;
    END
  END wd_in[42]
  PIN wd_in[43]
    DIRECTION INPUT ;
    USE SIGNAL ;
    SHAPE ABUTMENT ;
    PORT
      LAYER M4 ;
      RECT 0.000 102.192 0.024 102.216 ;
    END
  END wd_in[43]
  PIN wd_in[44]
    DIRECTION INPUT ;
    USE SIGNAL ;
    SHAPE ABUTMENT ;
    PORT
      LAYER M4 ;
      RECT 0.000 102.768 0.024 102.792 ;
    END
  END wd_in[44]
  PIN wd_in[45]
    DIRECTION INPUT ;
    USE SIGNAL ;
    SHAPE ABUTMENT ;
    PORT
      LAYER M4 ;
      RECT 0.000 103.344 0.024 103.368 ;
    END
  END wd_in[45]
  PIN wd_in[46]
    DIRECTION INPUT ;
    USE SIGNAL ;
    SHAPE ABUTMENT ;
    PORT
      LAYER M4 ;
      RECT 0.000 103.920 0.024 103.944 ;
    END
  END wd_in[46]
  PIN wd_in[47]
    DIRECTION INPUT ;
    USE SIGNAL ;
    SHAPE ABUTMENT ;
    PORT
      LAYER M4 ;
      RECT 0.000 104.496 0.024 104.520 ;
    END
  END wd_in[47]
  PIN wd_in[48]
    DIRECTION INPUT ;
    USE SIGNAL ;
    SHAPE ABUTMENT ;
    PORT
      LAYER M4 ;
      RECT 0.000 105.072 0.024 105.096 ;
    END
  END wd_in[48]
  PIN wd_in[49]
    DIRECTION INPUT ;
    USE SIGNAL ;
    SHAPE ABUTMENT ;
    PORT
      LAYER M4 ;
      RECT 0.000 105.648 0.024 105.672 ;
    END
  END wd_in[49]
  PIN wd_in[50]
    DIRECTION INPUT ;
    USE SIGNAL ;
    SHAPE ABUTMENT ;
    PORT
      LAYER M4 ;
      RECT 0.000 106.224 0.024 106.248 ;
    END
  END wd_in[50]
  PIN wd_in[51]
    DIRECTION INPUT ;
    USE SIGNAL ;
    SHAPE ABUTMENT ;
    PORT
      LAYER M4 ;
      RECT 0.000 106.800 0.024 106.824 ;
    END
  END wd_in[51]
  PIN wd_in[52]
    DIRECTION INPUT ;
    USE SIGNAL ;
    SHAPE ABUTMENT ;
    PORT
      LAYER M4 ;
      RECT 0.000 107.376 0.024 107.400 ;
    END
  END wd_in[52]
  PIN wd_in[53]
    DIRECTION INPUT ;
    USE SIGNAL ;
    SHAPE ABUTMENT ;
    PORT
      LAYER M4 ;
      RECT 0.000 107.952 0.024 107.976 ;
    END
  END wd_in[53]
  PIN wd_in[54]
    DIRECTION INPUT ;
    USE SIGNAL ;
    SHAPE ABUTMENT ;
    PORT
      LAYER M4 ;
      RECT 0.000 108.528 0.024 108.552 ;
    END
  END wd_in[54]
  PIN wd_in[55]
    DIRECTION INPUT ;
    USE SIGNAL ;
    SHAPE ABUTMENT ;
    PORT
      LAYER M4 ;
      RECT 0.000 109.104 0.024 109.128 ;
    END
  END wd_in[55]
  PIN wd_in[56]
    DIRECTION INPUT ;
    USE SIGNAL ;
    SHAPE ABUTMENT ;
    PORT
      LAYER M4 ;
      RECT 0.000 109.680 0.024 109.704 ;
    END
  END wd_in[56]
  PIN wd_in[57]
    DIRECTION INPUT ;
    USE SIGNAL ;
    SHAPE ABUTMENT ;
    PORT
      LAYER M4 ;
      RECT 0.000 110.256 0.024 110.280 ;
    END
  END wd_in[57]
  PIN wd_in[58]
    DIRECTION INPUT ;
    USE SIGNAL ;
    SHAPE ABUTMENT ;
    PORT
      LAYER M4 ;
      RECT 0.000 110.832 0.024 110.856 ;
    END
  END wd_in[58]
  PIN wd_in[59]
    DIRECTION INPUT ;
    USE SIGNAL ;
    SHAPE ABUTMENT ;
    PORT
      LAYER M4 ;
      RECT 0.000 111.408 0.024 111.432 ;
    END
  END wd_in[59]
  PIN wd_in[60]
    DIRECTION INPUT ;
    USE SIGNAL ;
    SHAPE ABUTMENT ;
    PORT
      LAYER M4 ;
      RECT 0.000 111.984 0.024 112.008 ;
    END
  END wd_in[60]
  PIN wd_in[61]
    DIRECTION INPUT ;
    USE SIGNAL ;
    SHAPE ABUTMENT ;
    PORT
      LAYER M4 ;
      RECT 0.000 112.560 0.024 112.584 ;
    END
  END wd_in[61]
  PIN wd_in[62]
    DIRECTION INPUT ;
    USE SIGNAL ;
    SHAPE ABUTMENT ;
    PORT
      LAYER M4 ;
      RECT 0.000 113.136 0.024 113.160 ;
    END
  END wd_in[62]
  PIN wd_in[63]
    DIRECTION INPUT ;
    USE SIGNAL ;
    SHAPE ABUTMENT ;
    PORT
      LAYER M4 ;
      RECT 0.000 113.712 0.024 113.736 ;
    END
  END wd_in[63]
  PIN wd_in[64]
    DIRECTION INPUT ;
    USE SIGNAL ;
    SHAPE ABUTMENT ;
    PORT
      LAYER M4 ;
      RECT 0.000 114.288 0.024 114.312 ;
    END
  END wd_in[64]
  PIN wd_in[65]
    DIRECTION INPUT ;
    USE SIGNAL ;
    SHAPE ABUTMENT ;
    PORT
      LAYER M4 ;
      RECT 0.000 114.864 0.024 114.888 ;
    END
  END wd_in[65]
  PIN wd_in[66]
    DIRECTION INPUT ;
    USE SIGNAL ;
    SHAPE ABUTMENT ;
    PORT
      LAYER M4 ;
      RECT 0.000 115.440 0.024 115.464 ;
    END
  END wd_in[66]
  PIN wd_in[67]
    DIRECTION INPUT ;
    USE SIGNAL ;
    SHAPE ABUTMENT ;
    PORT
      LAYER M4 ;
      RECT 0.000 116.016 0.024 116.040 ;
    END
  END wd_in[67]
  PIN wd_in[68]
    DIRECTION INPUT ;
    USE SIGNAL ;
    SHAPE ABUTMENT ;
    PORT
      LAYER M4 ;
      RECT 0.000 116.592 0.024 116.616 ;
    END
  END wd_in[68]
  PIN wd_in[69]
    DIRECTION INPUT ;
    USE SIGNAL ;
    SHAPE ABUTMENT ;
    PORT
      LAYER M4 ;
      RECT 0.000 117.168 0.024 117.192 ;
    END
  END wd_in[69]
  PIN wd_in[70]
    DIRECTION INPUT ;
    USE SIGNAL ;
    SHAPE ABUTMENT ;
    PORT
      LAYER M4 ;
      RECT 0.000 117.744 0.024 117.768 ;
    END
  END wd_in[70]
  PIN wd_in[71]
    DIRECTION INPUT ;
    USE SIGNAL ;
    SHAPE ABUTMENT ;
    PORT
      LAYER M4 ;
      RECT 0.000 118.320 0.024 118.344 ;
    END
  END wd_in[71]
  PIN wd_in[72]
    DIRECTION INPUT ;
    USE SIGNAL ;
    SHAPE ABUTMENT ;
    PORT
      LAYER M4 ;
      RECT 0.000 118.896 0.024 118.920 ;
    END
  END wd_in[72]
  PIN wd_in[73]
    DIRECTION INPUT ;
    USE SIGNAL ;
    SHAPE ABUTMENT ;
    PORT
      LAYER M4 ;
      RECT 0.000 119.472 0.024 119.496 ;
    END
  END wd_in[73]
  PIN wd_in[74]
    DIRECTION INPUT ;
    USE SIGNAL ;
    SHAPE ABUTMENT ;
    PORT
      LAYER M4 ;
      RECT 0.000 120.048 0.024 120.072 ;
    END
  END wd_in[74]
  PIN wd_in[75]
    DIRECTION INPUT ;
    USE SIGNAL ;
    SHAPE ABUTMENT ;
    PORT
      LAYER M4 ;
      RECT 0.000 120.624 0.024 120.648 ;
    END
  END wd_in[75]
  PIN wd_in[76]
    DIRECTION INPUT ;
    USE SIGNAL ;
    SHAPE ABUTMENT ;
    PORT
      LAYER M4 ;
      RECT 0.000 121.200 0.024 121.224 ;
    END
  END wd_in[76]
  PIN wd_in[77]
    DIRECTION INPUT ;
    USE SIGNAL ;
    SHAPE ABUTMENT ;
    PORT
      LAYER M4 ;
      RECT 0.000 121.776 0.024 121.800 ;
    END
  END wd_in[77]
  PIN wd_in[78]
    DIRECTION INPUT ;
    USE SIGNAL ;
    SHAPE ABUTMENT ;
    PORT
      LAYER M4 ;
      RECT 0.000 122.352 0.024 122.376 ;
    END
  END wd_in[78]
  PIN wd_in[79]
    DIRECTION INPUT ;
    USE SIGNAL ;
    SHAPE ABUTMENT ;
    PORT
      LAYER M4 ;
      RECT 0.000 122.928 0.024 122.952 ;
    END
  END wd_in[79]
  PIN wd_in[80]
    DIRECTION INPUT ;
    USE SIGNAL ;
    SHAPE ABUTMENT ;
    PORT
      LAYER M4 ;
      RECT 0.000 123.504 0.024 123.528 ;
    END
  END wd_in[80]
  PIN wd_in[81]
    DIRECTION INPUT ;
    USE SIGNAL ;
    SHAPE ABUTMENT ;
    PORT
      LAYER M4 ;
      RECT 0.000 124.080 0.024 124.104 ;
    END
  END wd_in[81]
  PIN wd_in[82]
    DIRECTION INPUT ;
    USE SIGNAL ;
    SHAPE ABUTMENT ;
    PORT
      LAYER M4 ;
      RECT 0.000 124.656 0.024 124.680 ;
    END
  END wd_in[82]
  PIN wd_in[83]
    DIRECTION INPUT ;
    USE SIGNAL ;
    SHAPE ABUTMENT ;
    PORT
      LAYER M4 ;
      RECT 0.000 125.232 0.024 125.256 ;
    END
  END wd_in[83]
  PIN wd_in[84]
    DIRECTION INPUT ;
    USE SIGNAL ;
    SHAPE ABUTMENT ;
    PORT
      LAYER M4 ;
      RECT 0.000 125.808 0.024 125.832 ;
    END
  END wd_in[84]
  PIN wd_in[85]
    DIRECTION INPUT ;
    USE SIGNAL ;
    SHAPE ABUTMENT ;
    PORT
      LAYER M4 ;
      RECT 0.000 126.384 0.024 126.408 ;
    END
  END wd_in[85]
  PIN wd_in[86]
    DIRECTION INPUT ;
    USE SIGNAL ;
    SHAPE ABUTMENT ;
    PORT
      LAYER M4 ;
      RECT 0.000 126.960 0.024 126.984 ;
    END
  END wd_in[86]
  PIN wd_in[87]
    DIRECTION INPUT ;
    USE SIGNAL ;
    SHAPE ABUTMENT ;
    PORT
      LAYER M4 ;
      RECT 0.000 127.536 0.024 127.560 ;
    END
  END wd_in[87]
  PIN wd_in[88]
    DIRECTION INPUT ;
    USE SIGNAL ;
    SHAPE ABUTMENT ;
    PORT
      LAYER M4 ;
      RECT 0.000 128.112 0.024 128.136 ;
    END
  END wd_in[88]
  PIN wd_in[89]
    DIRECTION INPUT ;
    USE SIGNAL ;
    SHAPE ABUTMENT ;
    PORT
      LAYER M4 ;
      RECT 0.000 128.688 0.024 128.712 ;
    END
  END wd_in[89]
  PIN wd_in[90]
    DIRECTION INPUT ;
    USE SIGNAL ;
    SHAPE ABUTMENT ;
    PORT
      LAYER M4 ;
      RECT 0.000 129.264 0.024 129.288 ;
    END
  END wd_in[90]
  PIN wd_in[91]
    DIRECTION INPUT ;
    USE SIGNAL ;
    SHAPE ABUTMENT ;
    PORT
      LAYER M4 ;
      RECT 0.000 129.840 0.024 129.864 ;
    END
  END wd_in[91]
  PIN wd_in[92]
    DIRECTION INPUT ;
    USE SIGNAL ;
    SHAPE ABUTMENT ;
    PORT
      LAYER M4 ;
      RECT 0.000 130.416 0.024 130.440 ;
    END
  END wd_in[92]
  PIN wd_in[93]
    DIRECTION INPUT ;
    USE SIGNAL ;
    SHAPE ABUTMENT ;
    PORT
      LAYER M4 ;
      RECT 0.000 130.992 0.024 131.016 ;
    END
  END wd_in[93]
  PIN wd_in[94]
    DIRECTION INPUT ;
    USE SIGNAL ;
    SHAPE ABUTMENT ;
    PORT
      LAYER M4 ;
      RECT 0.000 131.568 0.024 131.592 ;
    END
  END wd_in[94]
  PIN wd_in[95]
    DIRECTION INPUT ;
    USE SIGNAL ;
    SHAPE ABUTMENT ;
    PORT
      LAYER M4 ;
      RECT 0.000 132.144 0.024 132.168 ;
    END
  END wd_in[95]
  PIN wd_in[96]
    DIRECTION INPUT ;
    USE SIGNAL ;
    SHAPE ABUTMENT ;
    PORT
      LAYER M4 ;
      RECT 0.000 132.720 0.024 132.744 ;
    END
  END wd_in[96]
  PIN wd_in[97]
    DIRECTION INPUT ;
    USE SIGNAL ;
    SHAPE ABUTMENT ;
    PORT
      LAYER M4 ;
      RECT 0.000 133.296 0.024 133.320 ;
    END
  END wd_in[97]
  PIN wd_in[98]
    DIRECTION INPUT ;
    USE SIGNAL ;
    SHAPE ABUTMENT ;
    PORT
      LAYER M4 ;
      RECT 0.000 133.872 0.024 133.896 ;
    END
  END wd_in[98]
  PIN wd_in[99]
    DIRECTION INPUT ;
    USE SIGNAL ;
    SHAPE ABUTMENT ;
    PORT
      LAYER M4 ;
      RECT 0.000 134.448 0.024 134.472 ;
    END
  END wd_in[99]
  PIN wd_in[100]
    DIRECTION INPUT ;
    USE SIGNAL ;
    SHAPE ABUTMENT ;
    PORT
      LAYER M4 ;
      RECT 0.000 135.024 0.024 135.048 ;
    END
  END wd_in[100]
  PIN wd_in[101]
    DIRECTION INPUT ;
    USE SIGNAL ;
    SHAPE ABUTMENT ;
    PORT
      LAYER M4 ;
      RECT 0.000 135.600 0.024 135.624 ;
    END
  END wd_in[101]
  PIN wd_in[102]
    DIRECTION INPUT ;
    USE SIGNAL ;
    SHAPE ABUTMENT ;
    PORT
      LAYER M4 ;
      RECT 0.000 136.176 0.024 136.200 ;
    END
  END wd_in[102]
  PIN wd_in[103]
    DIRECTION INPUT ;
    USE SIGNAL ;
    SHAPE ABUTMENT ;
    PORT
      LAYER M4 ;
      RECT 0.000 136.752 0.024 136.776 ;
    END
  END wd_in[103]
  PIN wd_in[104]
    DIRECTION INPUT ;
    USE SIGNAL ;
    SHAPE ABUTMENT ;
    PORT
      LAYER M4 ;
      RECT 0.000 137.328 0.024 137.352 ;
    END
  END wd_in[104]
  PIN wd_in[105]
    DIRECTION INPUT ;
    USE SIGNAL ;
    SHAPE ABUTMENT ;
    PORT
      LAYER M4 ;
      RECT 0.000 137.904 0.024 137.928 ;
    END
  END wd_in[105]
  PIN wd_in[106]
    DIRECTION INPUT ;
    USE SIGNAL ;
    SHAPE ABUTMENT ;
    PORT
      LAYER M4 ;
      RECT 0.000 138.480 0.024 138.504 ;
    END
  END wd_in[106]
  PIN wd_in[107]
    DIRECTION INPUT ;
    USE SIGNAL ;
    SHAPE ABUTMENT ;
    PORT
      LAYER M4 ;
      RECT 0.000 139.056 0.024 139.080 ;
    END
  END wd_in[107]
  PIN wd_in[108]
    DIRECTION INPUT ;
    USE SIGNAL ;
    SHAPE ABUTMENT ;
    PORT
      LAYER M4 ;
      RECT 0.000 139.632 0.024 139.656 ;
    END
  END wd_in[108]
  PIN wd_in[109]
    DIRECTION INPUT ;
    USE SIGNAL ;
    SHAPE ABUTMENT ;
    PORT
      LAYER M4 ;
      RECT 0.000 140.208 0.024 140.232 ;
    END
  END wd_in[109]
  PIN wd_in[110]
    DIRECTION INPUT ;
    USE SIGNAL ;
    SHAPE ABUTMENT ;
    PORT
      LAYER M4 ;
      RECT 0.000 140.784 0.024 140.808 ;
    END
  END wd_in[110]
  PIN wd_in[111]
    DIRECTION INPUT ;
    USE SIGNAL ;
    SHAPE ABUTMENT ;
    PORT
      LAYER M4 ;
      RECT 0.000 141.360 0.024 141.384 ;
    END
  END wd_in[111]
  PIN wd_in[112]
    DIRECTION INPUT ;
    USE SIGNAL ;
    SHAPE ABUTMENT ;
    PORT
      LAYER M4 ;
      RECT 0.000 141.936 0.024 141.960 ;
    END
  END wd_in[112]
  PIN wd_in[113]
    DIRECTION INPUT ;
    USE SIGNAL ;
    SHAPE ABUTMENT ;
    PORT
      LAYER M4 ;
      RECT 0.000 142.512 0.024 142.536 ;
    END
  END wd_in[113]
  PIN wd_in[114]
    DIRECTION INPUT ;
    USE SIGNAL ;
    SHAPE ABUTMENT ;
    PORT
      LAYER M4 ;
      RECT 0.000 143.088 0.024 143.112 ;
    END
  END wd_in[114]
  PIN wd_in[115]
    DIRECTION INPUT ;
    USE SIGNAL ;
    SHAPE ABUTMENT ;
    PORT
      LAYER M4 ;
      RECT 0.000 143.664 0.024 143.688 ;
    END
  END wd_in[115]
  PIN wd_in[116]
    DIRECTION INPUT ;
    USE SIGNAL ;
    SHAPE ABUTMENT ;
    PORT
      LAYER M4 ;
      RECT 0.000 144.240 0.024 144.264 ;
    END
  END wd_in[116]
  PIN wd_in[117]
    DIRECTION INPUT ;
    USE SIGNAL ;
    SHAPE ABUTMENT ;
    PORT
      LAYER M4 ;
      RECT 0.000 144.816 0.024 144.840 ;
    END
  END wd_in[117]
  PIN wd_in[118]
    DIRECTION INPUT ;
    USE SIGNAL ;
    SHAPE ABUTMENT ;
    PORT
      LAYER M4 ;
      RECT 0.000 145.392 0.024 145.416 ;
    END
  END wd_in[118]
  PIN wd_in[119]
    DIRECTION INPUT ;
    USE SIGNAL ;
    SHAPE ABUTMENT ;
    PORT
      LAYER M4 ;
      RECT 0.000 145.968 0.024 145.992 ;
    END
  END wd_in[119]
  PIN wd_in[120]
    DIRECTION INPUT ;
    USE SIGNAL ;
    SHAPE ABUTMENT ;
    PORT
      LAYER M4 ;
      RECT 0.000 146.544 0.024 146.568 ;
    END
  END wd_in[120]
  PIN wd_in[121]
    DIRECTION INPUT ;
    USE SIGNAL ;
    SHAPE ABUTMENT ;
    PORT
      LAYER M4 ;
      RECT 0.000 147.120 0.024 147.144 ;
    END
  END wd_in[121]
  PIN wd_in[122]
    DIRECTION INPUT ;
    USE SIGNAL ;
    SHAPE ABUTMENT ;
    PORT
      LAYER M4 ;
      RECT 0.000 147.696 0.024 147.720 ;
    END
  END wd_in[122]
  PIN wd_in[123]
    DIRECTION INPUT ;
    USE SIGNAL ;
    SHAPE ABUTMENT ;
    PORT
      LAYER M4 ;
      RECT 0.000 148.272 0.024 148.296 ;
    END
  END wd_in[123]
  PIN wd_in[124]
    DIRECTION INPUT ;
    USE SIGNAL ;
    SHAPE ABUTMENT ;
    PORT
      LAYER M4 ;
      RECT 0.000 148.848 0.024 148.872 ;
    END
  END wd_in[124]
  PIN wd_in[125]
    DIRECTION INPUT ;
    USE SIGNAL ;
    SHAPE ABUTMENT ;
    PORT
      LAYER M4 ;
      RECT 0.000 149.424 0.024 149.448 ;
    END
  END wd_in[125]
  PIN wd_in[126]
    DIRECTION INPUT ;
    USE SIGNAL ;
    SHAPE ABUTMENT ;
    PORT
      LAYER M4 ;
      RECT 0.000 150.000 0.024 150.024 ;
    END
  END wd_in[126]
  PIN wd_in[127]
    DIRECTION INPUT ;
    USE SIGNAL ;
    SHAPE ABUTMENT ;
    PORT
      LAYER M4 ;
      RECT 0.000 150.576 0.024 150.600 ;
    END
  END wd_in[127]
  PIN addr_in[0]
    DIRECTION INPUT ;
    USE SIGNAL ;
    SHAPE ABUTMENT ;
    PORT
      LAYER M4 ;
      RECT 0.000 154.800 0.024 154.824 ;
    END
  END addr_in[0]
  PIN addr_in[1]
    DIRECTION INPUT ;
    USE SIGNAL ;
    SHAPE ABUTMENT ;
    PORT
      LAYER M4 ;
      RECT 0.000 155.376 0.024 155.400 ;
    END
  END addr_in[1]
  PIN addr_in[2]
    DIRECTION INPUT ;
    USE SIGNAL ;
    SHAPE ABUTMENT ;
    PORT
      LAYER M4 ;
      RECT 0.000 155.952 0.024 155.976 ;
    END
  END addr_in[2]
  PIN addr_in[3]
    DIRECTION INPUT ;
    USE SIGNAL ;
    SHAPE ABUTMENT ;
    PORT
      LAYER M4 ;
      RECT 0.000 156.528 0.024 156.552 ;
    END
  END addr_in[3]
  PIN addr_in[4]
    DIRECTION INPUT ;
    USE SIGNAL ;
    SHAPE ABUTMENT ;
    PORT
      LAYER M4 ;
      RECT 0.000 157.104 0.024 157.128 ;
    END
  END addr_in[4]
  PIN addr_in[5]
    DIRECTION INPUT ;
    USE SIGNAL ;
    SHAPE ABUTMENT ;
    PORT
      LAYER M4 ;
      RECT 0.000 157.680 0.024 157.704 ;
    END
  END addr_in[5]
  PIN addr_in[6]
    DIRECTION INPUT ;
    USE SIGNAL ;
    SHAPE ABUTMENT ;
    PORT
      LAYER M4 ;
      RECT 0.000 158.256 0.024 158.280 ;
    END
  END addr_in[6]
  PIN addr_in[7]
    DIRECTION INPUT ;
    USE SIGNAL ;
    SHAPE ABUTMENT ;
    PORT
      LAYER M4 ;
      RECT 0.000 158.832 0.024 158.856 ;
    END
  END addr_in[7]
  PIN addr_in[8]
    DIRECTION INPUT ;
    USE SIGNAL ;
    SHAPE ABUTMENT ;
    PORT
      LAYER M4 ;
      RECT 0.000 159.408 0.024 159.432 ;
    END
  END addr_in[8]
  PIN addr_in[9]
    DIRECTION INPUT ;
    USE SIGNAL ;
    SHAPE ABUTMENT ;
    PORT
      LAYER M4 ;
      RECT 0.000 159.984 0.024 160.008 ;
    END
  END addr_in[9]
  PIN addr_in[10]
    DIRECTION INPUT ;
    USE SIGNAL ;
    SHAPE ABUTMENT ;
    PORT
      LAYER M4 ;
      RECT 0.000 160.560 0.024 160.584 ;
    END
  END addr_in[10]
  PIN we_in
    DIRECTION INPUT ;
    USE SIGNAL ;
    SHAPE ABUTMENT ;
    PORT
      LAYER M4 ;
      RECT 0.000 164.784 0.024 164.808 ;
    END
  END we_in
  PIN clk
    DIRECTION INPUT ;
    USE SIGNAL ;
    SHAPE ABUTMENT ;
    PORT
      LAYER M4 ;
      RECT 0.000 165.360 0.024 165.384 ;
    END
  END clk
  PIN ce_in
    DIRECTION INPUT ;
    USE SIGNAL ;
    SHAPE ABUTMENT ;
    PORT
      LAYER M4 ;
      RECT 0.000 165.936 0.024 165.960 ;
    END
  END ce_in
  PIN VDD
    DIRECTION INOUT ;
    USE POWER ;
    PORT
      LAYER M4 ;
      RECT 0.048 0.384 66.452 0.480 ;
      RECT 0.048 1.152 66.452 1.248 ;
      RECT 0.048 1.920 66.452 2.016 ;
      RECT 0.048 2.688 66.452 2.784 ;
      RECT 0.048 3.456 66.452 3.552 ;
      RECT 0.048 4.224 66.452 4.320 ;
      RECT 0.048 4.992 66.452 5.088 ;
      RECT 0.048 5.760 66.452 5.856 ;
      RECT 0.048 6.528 66.452 6.624 ;
      RECT 0.048 7.296 66.452 7.392 ;
      RECT 0.048 8.064 66.452 8.160 ;
      RECT 0.048 8.832 66.452 8.928 ;
      RECT 0.048 9.600 66.452 9.696 ;
      RECT 0.048 10.368 66.452 10.464 ;
      RECT 0.048 11.136 66.452 11.232 ;
      RECT 0.048 11.904 66.452 12.000 ;
      RECT 0.048 12.672 66.452 12.768 ;
      RECT 0.048 13.440 66.452 13.536 ;
      RECT 0.048 14.208 66.452 14.304 ;
      RECT 0.048 14.976 66.452 15.072 ;
      RECT 0.048 15.744 66.452 15.840 ;
      RECT 0.048 16.512 66.452 16.608 ;
      RECT 0.048 17.280 66.452 17.376 ;
      RECT 0.048 18.048 66.452 18.144 ;
      RECT 0.048 18.816 66.452 18.912 ;
      RECT 0.048 19.584 66.452 19.680 ;
      RECT 0.048 20.352 66.452 20.448 ;
      RECT 0.048 21.120 66.452 21.216 ;
      RECT 0.048 21.888 66.452 21.984 ;
      RECT 0.048 22.656 66.452 22.752 ;
      RECT 0.048 23.424 66.452 23.520 ;
      RECT 0.048 24.192 66.452 24.288 ;
      RECT 0.048 24.960 66.452 25.056 ;
      RECT 0.048 25.728 66.452 25.824 ;
      RECT 0.048 26.496 66.452 26.592 ;
      RECT 0.048 27.264 66.452 27.360 ;
      RECT 0.048 28.032 66.452 28.128 ;
      RECT 0.048 28.800 66.452 28.896 ;
      RECT 0.048 29.568 66.452 29.664 ;
      RECT 0.048 30.336 66.452 30.432 ;
      RECT 0.048 31.104 66.452 31.200 ;
      RECT 0.048 31.872 66.452 31.968 ;
      RECT 0.048 32.640 66.452 32.736 ;
      RECT 0.048 33.408 66.452 33.504 ;
      RECT 0.048 34.176 66.452 34.272 ;
      RECT 0.048 34.944 66.452 35.040 ;
      RECT 0.048 35.712 66.452 35.808 ;
      RECT 0.048 36.480 66.452 36.576 ;
      RECT 0.048 37.248 66.452 37.344 ;
      RECT 0.048 38.016 66.452 38.112 ;
      RECT 0.048 38.784 66.452 38.880 ;
      RECT 0.048 39.552 66.452 39.648 ;
      RECT 0.048 40.320 66.452 40.416 ;
      RECT 0.048 41.088 66.452 41.184 ;
      RECT 0.048 41.856 66.452 41.952 ;
      RECT 0.048 42.624 66.452 42.720 ;
      RECT 0.048 43.392 66.452 43.488 ;
      RECT 0.048 44.160 66.452 44.256 ;
      RECT 0.048 44.928 66.452 45.024 ;
      RECT 0.048 45.696 66.452 45.792 ;
      RECT 0.048 46.464 66.452 46.560 ;
      RECT 0.048 47.232 66.452 47.328 ;
      RECT 0.048 48.000 66.452 48.096 ;
      RECT 0.048 48.768 66.452 48.864 ;
      RECT 0.048 49.536 66.452 49.632 ;
      RECT 0.048 50.304 66.452 50.400 ;
      RECT 0.048 51.072 66.452 51.168 ;
      RECT 0.048 51.840 66.452 51.936 ;
      RECT 0.048 52.608 66.452 52.704 ;
      RECT 0.048 53.376 66.452 53.472 ;
      RECT 0.048 54.144 66.452 54.240 ;
      RECT 0.048 54.912 66.452 55.008 ;
      RECT 0.048 55.680 66.452 55.776 ;
      RECT 0.048 56.448 66.452 56.544 ;
      RECT 0.048 57.216 66.452 57.312 ;
      RECT 0.048 57.984 66.452 58.080 ;
      RECT 0.048 58.752 66.452 58.848 ;
      RECT 0.048 59.520 66.452 59.616 ;
      RECT 0.048 60.288 66.452 60.384 ;
      RECT 0.048 61.056 66.452 61.152 ;
      RECT 0.048 61.824 66.452 61.920 ;
      RECT 0.048 62.592 66.452 62.688 ;
      RECT 0.048 63.360 66.452 63.456 ;
      RECT 0.048 64.128 66.452 64.224 ;
      RECT 0.048 64.896 66.452 64.992 ;
      RECT 0.048 65.664 66.452 65.760 ;
      RECT 0.048 66.432 66.452 66.528 ;
      RECT 0.048 67.200 66.452 67.296 ;
      RECT 0.048 67.968 66.452 68.064 ;
      RECT 0.048 68.736 66.452 68.832 ;
      RECT 0.048 69.504 66.452 69.600 ;
      RECT 0.048 70.272 66.452 70.368 ;
      RECT 0.048 71.040 66.452 71.136 ;
      RECT 0.048 71.808 66.452 71.904 ;
      RECT 0.048 72.576 66.452 72.672 ;
      RECT 0.048 73.344 66.452 73.440 ;
      RECT 0.048 74.112 66.452 74.208 ;
      RECT 0.048 74.880 66.452 74.976 ;
      RECT 0.048 75.648 66.452 75.744 ;
      RECT 0.048 76.416 66.452 76.512 ;
      RECT 0.048 77.184 66.452 77.280 ;
      RECT 0.048 77.952 66.452 78.048 ;
      RECT 0.048 78.720 66.452 78.816 ;
      RECT 0.048 79.488 66.452 79.584 ;
      RECT 0.048 80.256 66.452 80.352 ;
      RECT 0.048 81.024 66.452 81.120 ;
      RECT 0.048 81.792 66.452 81.888 ;
      RECT 0.048 82.560 66.452 82.656 ;
      RECT 0.048 83.328 66.452 83.424 ;
      RECT 0.048 84.096 66.452 84.192 ;
      RECT 0.048 84.864 66.452 84.960 ;
      RECT 0.048 85.632 66.452 85.728 ;
      RECT 0.048 86.400 66.452 86.496 ;
      RECT 0.048 87.168 66.452 87.264 ;
      RECT 0.048 87.936 66.452 88.032 ;
      RECT 0.048 88.704 66.452 88.800 ;
      RECT 0.048 89.472 66.452 89.568 ;
      RECT 0.048 90.240 66.452 90.336 ;
      RECT 0.048 91.008 66.452 91.104 ;
      RECT 0.048 91.776 66.452 91.872 ;
      RECT 0.048 92.544 66.452 92.640 ;
      RECT 0.048 93.312 66.452 93.408 ;
      RECT 0.048 94.080 66.452 94.176 ;
      RECT 0.048 94.848 66.452 94.944 ;
      RECT 0.048 95.616 66.452 95.712 ;
      RECT 0.048 96.384 66.452 96.480 ;
      RECT 0.048 97.152 66.452 97.248 ;
      RECT 0.048 97.920 66.452 98.016 ;
      RECT 0.048 98.688 66.452 98.784 ;
      RECT 0.048 99.456 66.452 99.552 ;
      RECT 0.048 100.224 66.452 100.320 ;
      RECT 0.048 100.992 66.452 101.088 ;
      RECT 0.048 101.760 66.452 101.856 ;
      RECT 0.048 102.528 66.452 102.624 ;
      RECT 0.048 103.296 66.452 103.392 ;
      RECT 0.048 104.064 66.452 104.160 ;
      RECT 0.048 104.832 66.452 104.928 ;
      RECT 0.048 105.600 66.452 105.696 ;
      RECT 0.048 106.368 66.452 106.464 ;
      RECT 0.048 107.136 66.452 107.232 ;
      RECT 0.048 107.904 66.452 108.000 ;
      RECT 0.048 108.672 66.452 108.768 ;
      RECT 0.048 109.440 66.452 109.536 ;
      RECT 0.048 110.208 66.452 110.304 ;
      RECT 0.048 110.976 66.452 111.072 ;
      RECT 0.048 111.744 66.452 111.840 ;
      RECT 0.048 112.512 66.452 112.608 ;
      RECT 0.048 113.280 66.452 113.376 ;
      RECT 0.048 114.048 66.452 114.144 ;
      RECT 0.048 114.816 66.452 114.912 ;
      RECT 0.048 115.584 66.452 115.680 ;
      RECT 0.048 116.352 66.452 116.448 ;
      RECT 0.048 117.120 66.452 117.216 ;
      RECT 0.048 117.888 66.452 117.984 ;
      RECT 0.048 118.656 66.452 118.752 ;
      RECT 0.048 119.424 66.452 119.520 ;
      RECT 0.048 120.192 66.452 120.288 ;
      RECT 0.048 120.960 66.452 121.056 ;
      RECT 0.048 121.728 66.452 121.824 ;
      RECT 0.048 122.496 66.452 122.592 ;
      RECT 0.048 123.264 66.452 123.360 ;
      RECT 0.048 124.032 66.452 124.128 ;
      RECT 0.048 124.800 66.452 124.896 ;
      RECT 0.048 125.568 66.452 125.664 ;
      RECT 0.048 126.336 66.452 126.432 ;
      RECT 0.048 127.104 66.452 127.200 ;
      RECT 0.048 127.872 66.452 127.968 ;
      RECT 0.048 128.640 66.452 128.736 ;
      RECT 0.048 129.408 66.452 129.504 ;
      RECT 0.048 130.176 66.452 130.272 ;
      RECT 0.048 130.944 66.452 131.040 ;
      RECT 0.048 131.712 66.452 131.808 ;
      RECT 0.048 132.480 66.452 132.576 ;
      RECT 0.048 133.248 66.452 133.344 ;
      RECT 0.048 134.016 66.452 134.112 ;
      RECT 0.048 134.784 66.452 134.880 ;
      RECT 0.048 135.552 66.452 135.648 ;
      RECT 0.048 136.320 66.452 136.416 ;
      RECT 0.048 137.088 66.452 137.184 ;
      RECT 0.048 137.856 66.452 137.952 ;
      RECT 0.048 138.624 66.452 138.720 ;
      RECT 0.048 139.392 66.452 139.488 ;
      RECT 0.048 140.160 66.452 140.256 ;
      RECT 0.048 140.928 66.452 141.024 ;
      RECT 0.048 141.696 66.452 141.792 ;
      RECT 0.048 142.464 66.452 142.560 ;
      RECT 0.048 143.232 66.452 143.328 ;
      RECT 0.048 144.000 66.452 144.096 ;
      RECT 0.048 144.768 66.452 144.864 ;
      RECT 0.048 145.536 66.452 145.632 ;
      RECT 0.048 146.304 66.452 146.400 ;
      RECT 0.048 147.072 66.452 147.168 ;
      RECT 0.048 147.840 66.452 147.936 ;
      RECT 0.048 148.608 66.452 148.704 ;
      RECT 0.048 149.376 66.452 149.472 ;
      RECT 0.048 150.144 66.452 150.240 ;
      RECT 0.048 150.912 66.452 151.008 ;
      RECT 0.048 151.680 66.452 151.776 ;
      RECT 0.048 152.448 66.452 152.544 ;
      RECT 0.048 153.216 66.452 153.312 ;
      RECT 0.048 153.984 66.452 154.080 ;
      RECT 0.048 154.752 66.452 154.848 ;
      RECT 0.048 155.520 66.452 155.616 ;
      RECT 0.048 156.288 66.452 156.384 ;
      RECT 0.048 157.056 66.452 157.152 ;
      RECT 0.048 157.824 66.452 157.920 ;
      RECT 0.048 158.592 66.452 158.688 ;
      RECT 0.048 159.360 66.452 159.456 ;
      RECT 0.048 160.128 66.452 160.224 ;
      RECT 0.048 160.896 66.452 160.992 ;
      RECT 0.048 161.664 66.452 161.760 ;
      RECT 0.048 162.432 66.452 162.528 ;
      RECT 0.048 163.200 66.452 163.296 ;
      RECT 0.048 163.968 66.452 164.064 ;
      RECT 0.048 164.736 66.452 164.832 ;
      RECT 0.048 165.504 66.452 165.600 ;
      RECT 0.048 166.272 66.452 166.368 ;
    END
  END VDD
  PIN VSS
    DIRECTION INOUT ;
    USE GROUND ;
    PORT
      LAYER M4 ;
      RECT 0.048 0.000 66.452 0.096 ;
      RECT 0.048 0.768 66.452 0.864 ;
      RECT 0.048 1.536 66.452 1.632 ;
      RECT 0.048 2.304 66.452 2.400 ;
      RECT 0.048 3.072 66.452 3.168 ;
      RECT 0.048 3.840 66.452 3.936 ;
      RECT 0.048 4.608 66.452 4.704 ;
      RECT 0.048 5.376 66.452 5.472 ;
      RECT 0.048 6.144 66.452 6.240 ;
      RECT 0.048 6.912 66.452 7.008 ;
      RECT 0.048 7.680 66.452 7.776 ;
      RECT 0.048 8.448 66.452 8.544 ;
      RECT 0.048 9.216 66.452 9.312 ;
      RECT 0.048 9.984 66.452 10.080 ;
      RECT 0.048 10.752 66.452 10.848 ;
      RECT 0.048 11.520 66.452 11.616 ;
      RECT 0.048 12.288 66.452 12.384 ;
      RECT 0.048 13.056 66.452 13.152 ;
      RECT 0.048 13.824 66.452 13.920 ;
      RECT 0.048 14.592 66.452 14.688 ;
      RECT 0.048 15.360 66.452 15.456 ;
      RECT 0.048 16.128 66.452 16.224 ;
      RECT 0.048 16.896 66.452 16.992 ;
      RECT 0.048 17.664 66.452 17.760 ;
      RECT 0.048 18.432 66.452 18.528 ;
      RECT 0.048 19.200 66.452 19.296 ;
      RECT 0.048 19.968 66.452 20.064 ;
      RECT 0.048 20.736 66.452 20.832 ;
      RECT 0.048 21.504 66.452 21.600 ;
      RECT 0.048 22.272 66.452 22.368 ;
      RECT 0.048 23.040 66.452 23.136 ;
      RECT 0.048 23.808 66.452 23.904 ;
      RECT 0.048 24.576 66.452 24.672 ;
      RECT 0.048 25.344 66.452 25.440 ;
      RECT 0.048 26.112 66.452 26.208 ;
      RECT 0.048 26.880 66.452 26.976 ;
      RECT 0.048 27.648 66.452 27.744 ;
      RECT 0.048 28.416 66.452 28.512 ;
      RECT 0.048 29.184 66.452 29.280 ;
      RECT 0.048 29.952 66.452 30.048 ;
      RECT 0.048 30.720 66.452 30.816 ;
      RECT 0.048 31.488 66.452 31.584 ;
      RECT 0.048 32.256 66.452 32.352 ;
      RECT 0.048 33.024 66.452 33.120 ;
      RECT 0.048 33.792 66.452 33.888 ;
      RECT 0.048 34.560 66.452 34.656 ;
      RECT 0.048 35.328 66.452 35.424 ;
      RECT 0.048 36.096 66.452 36.192 ;
      RECT 0.048 36.864 66.452 36.960 ;
      RECT 0.048 37.632 66.452 37.728 ;
      RECT 0.048 38.400 66.452 38.496 ;
      RECT 0.048 39.168 66.452 39.264 ;
      RECT 0.048 39.936 66.452 40.032 ;
      RECT 0.048 40.704 66.452 40.800 ;
      RECT 0.048 41.472 66.452 41.568 ;
      RECT 0.048 42.240 66.452 42.336 ;
      RECT 0.048 43.008 66.452 43.104 ;
      RECT 0.048 43.776 66.452 43.872 ;
      RECT 0.048 44.544 66.452 44.640 ;
      RECT 0.048 45.312 66.452 45.408 ;
      RECT 0.048 46.080 66.452 46.176 ;
      RECT 0.048 46.848 66.452 46.944 ;
      RECT 0.048 47.616 66.452 47.712 ;
      RECT 0.048 48.384 66.452 48.480 ;
      RECT 0.048 49.152 66.452 49.248 ;
      RECT 0.048 49.920 66.452 50.016 ;
      RECT 0.048 50.688 66.452 50.784 ;
      RECT 0.048 51.456 66.452 51.552 ;
      RECT 0.048 52.224 66.452 52.320 ;
      RECT 0.048 52.992 66.452 53.088 ;
      RECT 0.048 53.760 66.452 53.856 ;
      RECT 0.048 54.528 66.452 54.624 ;
      RECT 0.048 55.296 66.452 55.392 ;
      RECT 0.048 56.064 66.452 56.160 ;
      RECT 0.048 56.832 66.452 56.928 ;
      RECT 0.048 57.600 66.452 57.696 ;
      RECT 0.048 58.368 66.452 58.464 ;
      RECT 0.048 59.136 66.452 59.232 ;
      RECT 0.048 59.904 66.452 60.000 ;
      RECT 0.048 60.672 66.452 60.768 ;
      RECT 0.048 61.440 66.452 61.536 ;
      RECT 0.048 62.208 66.452 62.304 ;
      RECT 0.048 62.976 66.452 63.072 ;
      RECT 0.048 63.744 66.452 63.840 ;
      RECT 0.048 64.512 66.452 64.608 ;
      RECT 0.048 65.280 66.452 65.376 ;
      RECT 0.048 66.048 66.452 66.144 ;
      RECT 0.048 66.816 66.452 66.912 ;
      RECT 0.048 67.584 66.452 67.680 ;
      RECT 0.048 68.352 66.452 68.448 ;
      RECT 0.048 69.120 66.452 69.216 ;
      RECT 0.048 69.888 66.452 69.984 ;
      RECT 0.048 70.656 66.452 70.752 ;
      RECT 0.048 71.424 66.452 71.520 ;
      RECT 0.048 72.192 66.452 72.288 ;
      RECT 0.048 72.960 66.452 73.056 ;
      RECT 0.048 73.728 66.452 73.824 ;
      RECT 0.048 74.496 66.452 74.592 ;
      RECT 0.048 75.264 66.452 75.360 ;
      RECT 0.048 76.032 66.452 76.128 ;
      RECT 0.048 76.800 66.452 76.896 ;
      RECT 0.048 77.568 66.452 77.664 ;
      RECT 0.048 78.336 66.452 78.432 ;
      RECT 0.048 79.104 66.452 79.200 ;
      RECT 0.048 79.872 66.452 79.968 ;
      RECT 0.048 80.640 66.452 80.736 ;
      RECT 0.048 81.408 66.452 81.504 ;
      RECT 0.048 82.176 66.452 82.272 ;
      RECT 0.048 82.944 66.452 83.040 ;
      RECT 0.048 83.712 66.452 83.808 ;
      RECT 0.048 84.480 66.452 84.576 ;
      RECT 0.048 85.248 66.452 85.344 ;
      RECT 0.048 86.016 66.452 86.112 ;
      RECT 0.048 86.784 66.452 86.880 ;
      RECT 0.048 87.552 66.452 87.648 ;
      RECT 0.048 88.320 66.452 88.416 ;
      RECT 0.048 89.088 66.452 89.184 ;
      RECT 0.048 89.856 66.452 89.952 ;
      RECT 0.048 90.624 66.452 90.720 ;
      RECT 0.048 91.392 66.452 91.488 ;
      RECT 0.048 92.160 66.452 92.256 ;
      RECT 0.048 92.928 66.452 93.024 ;
      RECT 0.048 93.696 66.452 93.792 ;
      RECT 0.048 94.464 66.452 94.560 ;
      RECT 0.048 95.232 66.452 95.328 ;
      RECT 0.048 96.000 66.452 96.096 ;
      RECT 0.048 96.768 66.452 96.864 ;
      RECT 0.048 97.536 66.452 97.632 ;
      RECT 0.048 98.304 66.452 98.400 ;
      RECT 0.048 99.072 66.452 99.168 ;
      RECT 0.048 99.840 66.452 99.936 ;
      RECT 0.048 100.608 66.452 100.704 ;
      RECT 0.048 101.376 66.452 101.472 ;
      RECT 0.048 102.144 66.452 102.240 ;
      RECT 0.048 102.912 66.452 103.008 ;
      RECT 0.048 103.680 66.452 103.776 ;
      RECT 0.048 104.448 66.452 104.544 ;
      RECT 0.048 105.216 66.452 105.312 ;
      RECT 0.048 105.984 66.452 106.080 ;
      RECT 0.048 106.752 66.452 106.848 ;
      RECT 0.048 107.520 66.452 107.616 ;
      RECT 0.048 108.288 66.452 108.384 ;
      RECT 0.048 109.056 66.452 109.152 ;
      RECT 0.048 109.824 66.452 109.920 ;
      RECT 0.048 110.592 66.452 110.688 ;
      RECT 0.048 111.360 66.452 111.456 ;
      RECT 0.048 112.128 66.452 112.224 ;
      RECT 0.048 112.896 66.452 112.992 ;
      RECT 0.048 113.664 66.452 113.760 ;
      RECT 0.048 114.432 66.452 114.528 ;
      RECT 0.048 115.200 66.452 115.296 ;
      RECT 0.048 115.968 66.452 116.064 ;
      RECT 0.048 116.736 66.452 116.832 ;
      RECT 0.048 117.504 66.452 117.600 ;
      RECT 0.048 118.272 66.452 118.368 ;
      RECT 0.048 119.040 66.452 119.136 ;
      RECT 0.048 119.808 66.452 119.904 ;
      RECT 0.048 120.576 66.452 120.672 ;
      RECT 0.048 121.344 66.452 121.440 ;
      RECT 0.048 122.112 66.452 122.208 ;
      RECT 0.048 122.880 66.452 122.976 ;
      RECT 0.048 123.648 66.452 123.744 ;
      RECT 0.048 124.416 66.452 124.512 ;
      RECT 0.048 125.184 66.452 125.280 ;
      RECT 0.048 125.952 66.452 126.048 ;
      RECT 0.048 126.720 66.452 126.816 ;
      RECT 0.048 127.488 66.452 127.584 ;
      RECT 0.048 128.256 66.452 128.352 ;
      RECT 0.048 129.024 66.452 129.120 ;
      RECT 0.048 129.792 66.452 129.888 ;
      RECT 0.048 130.560 66.452 130.656 ;
      RECT 0.048 131.328 66.452 131.424 ;
      RECT 0.048 132.096 66.452 132.192 ;
      RECT 0.048 132.864 66.452 132.960 ;
      RECT 0.048 133.632 66.452 133.728 ;
      RECT 0.048 134.400 66.452 134.496 ;
      RECT 0.048 135.168 66.452 135.264 ;
      RECT 0.048 135.936 66.452 136.032 ;
      RECT 0.048 136.704 66.452 136.800 ;
      RECT 0.048 137.472 66.452 137.568 ;
      RECT 0.048 138.240 66.452 138.336 ;
      RECT 0.048 139.008 66.452 139.104 ;
      RECT 0.048 139.776 66.452 139.872 ;
      RECT 0.048 140.544 66.452 140.640 ;
      RECT 0.048 141.312 66.452 141.408 ;
      RECT 0.048 142.080 66.452 142.176 ;
      RECT 0.048 142.848 66.452 142.944 ;
      RECT 0.048 143.616 66.452 143.712 ;
      RECT 0.048 144.384 66.452 144.480 ;
      RECT 0.048 145.152 66.452 145.248 ;
      RECT 0.048 145.920 66.452 146.016 ;
      RECT 0.048 146.688 66.452 146.784 ;
      RECT 0.048 147.456 66.452 147.552 ;
      RECT 0.048 148.224 66.452 148.320 ;
      RECT 0.048 148.992 66.452 149.088 ;
      RECT 0.048 149.760 66.452 149.856 ;
      RECT 0.048 150.528 66.452 150.624 ;
      RECT 0.048 151.296 66.452 151.392 ;
      RECT 0.048 152.064 66.452 152.160 ;
      RECT 0.048 152.832 66.452 152.928 ;
      RECT 0.048 153.600 66.452 153.696 ;
      RECT 0.048 154.368 66.452 154.464 ;
      RECT 0.048 155.136 66.452 155.232 ;
      RECT 0.048 155.904 66.452 156.000 ;
      RECT 0.048 156.672 66.452 156.768 ;
      RECT 0.048 157.440 66.452 157.536 ;
      RECT 0.048 158.208 66.452 158.304 ;
      RECT 0.048 158.976 66.452 159.072 ;
      RECT 0.048 159.744 66.452 159.840 ;
      RECT 0.048 160.512 66.452 160.608 ;
      RECT 0.048 161.280 66.452 161.376 ;
      RECT 0.048 162.048 66.452 162.144 ;
      RECT 0.048 162.816 66.452 162.912 ;
      RECT 0.048 163.584 66.452 163.680 ;
      RECT 0.048 164.352 66.452 164.448 ;
      RECT 0.048 165.120 66.452 165.216 ;
      RECT 0.048 165.888 66.452 165.984 ;
    END
  END VSS
  OBS
    LAYER M1 ;
    RECT 0 0 66.500 166.600 ;
    LAYER M2 ;
    RECT 0 0 66.500 166.600 ;
    LAYER M3 ;
    RECT 0 0 66.500 166.600 ;
    LAYER M4 ;
    RECT 0 0 66.500 166.600 ;
  END
END fakeram_2048x128

END LIBRARY
